VERSION 5.8 ;
BUSBITCHARS "[]" ;
DIVIDERCHAR "/" ;
UNITS
    DATABASE MICRONS 1000 ;
END UNITS

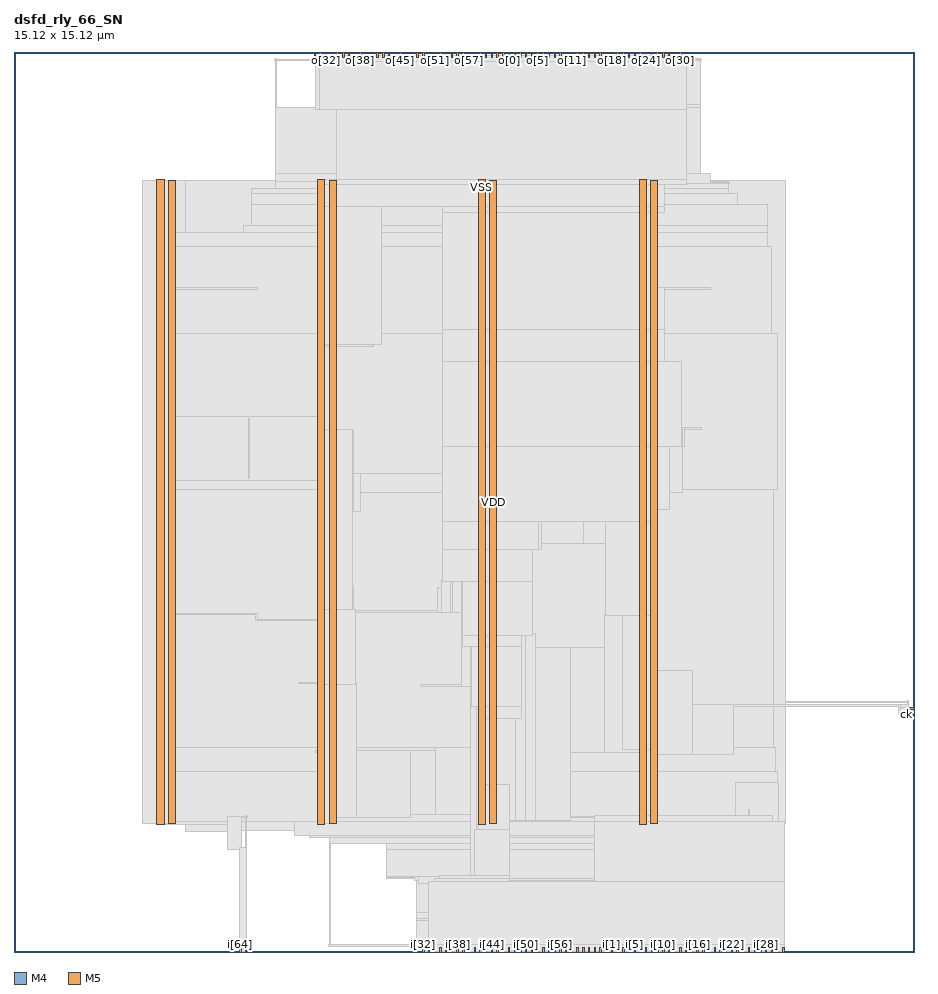
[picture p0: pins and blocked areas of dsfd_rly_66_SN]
MACRO dsfd_rly_66_SN
  FOREIGN dsfd_rly_66_SN 0 0 ;
  CLASS BLOCK ;
  SIZE 15.12 BY 15.12 ;
  PIN ck
    DIRECTION INPUT ;
    USE SIGNAL ;
    PORT
      LAYER M4 ;
        RECT  15.036 3.984 15.12 4.008 ;
    END
  END ck
  PIN i[0]
    DIRECTION INPUT ;
    USE SIGNAL ;
    PORT
      LAYER M5 ;
        RECT  9.936 0 9.96 0.084 ;
    END
  END i[0]
  PIN i[10]
    DIRECTION INPUT ;
    USE SIGNAL ;
    PORT
      LAYER M5 ;
        RECT  10.896 0 10.92 0.084 ;
    END
  END i[10]
  PIN i[11]
    DIRECTION INPUT ;
    USE SIGNAL ;
    PORT
      LAYER M5 ;
        RECT  10.992 0 11.016 0.084 ;
    END
  END i[11]
  PIN i[12]
    DIRECTION INPUT ;
    USE SIGNAL ;
    PORT
      LAYER M5 ;
        RECT  11.088 0 11.112 0.084 ;
    END
  END i[12]
  PIN i[13]
    DIRECTION INPUT ;
    USE SIGNAL ;
    PORT
      LAYER M5 ;
        RECT  11.184 0 11.208 0.084 ;
    END
  END i[13]
  PIN i[14]
    DIRECTION INPUT ;
    USE SIGNAL ;
    PORT
      LAYER M5 ;
        RECT  11.28 0 11.304 0.084 ;
    END
  END i[14]
  PIN i[15]
    DIRECTION INPUT ;
    USE SIGNAL ;
    PORT
      LAYER M5 ;
        RECT  11.376 0 11.4 0.084 ;
    END
  END i[15]
  PIN i[16]
    DIRECTION INPUT ;
    USE SIGNAL ;
    PORT
      LAYER M5 ;
        RECT  11.472 0 11.496 0.084 ;
    END
  END i[16]
  PIN i[17]
    DIRECTION INPUT ;
    USE SIGNAL ;
    PORT
      LAYER M5 ;
        RECT  11.568 0 11.592 0.084 ;
    END
  END i[17]
  PIN i[18]
    DIRECTION INPUT ;
    USE SIGNAL ;
    PORT
      LAYER M5 ;
        RECT  11.664 0 11.688 0.084 ;
    END
  END i[18]
  PIN i[19]
    DIRECTION INPUT ;
    USE SIGNAL ;
    PORT
      LAYER M5 ;
        RECT  11.76 0 11.784 0.084 ;
    END
  END i[19]
  PIN i[1]
    DIRECTION INPUT ;
    USE SIGNAL ;
    PORT
      LAYER M5 ;
        RECT  10.032 0 10.056 0.084 ;
    END
  END i[1]
  PIN i[20]
    DIRECTION INPUT ;
    USE SIGNAL ;
    PORT
      LAYER M5 ;
        RECT  11.856 0 11.88 0.084 ;
    END
  END i[20]
  PIN i[21]
    DIRECTION INPUT ;
    USE SIGNAL ;
    PORT
      LAYER M5 ;
        RECT  11.952 0 11.976 0.084 ;
    END
  END i[21]
  PIN i[22]
    DIRECTION INPUT ;
    USE SIGNAL ;
    PORT
      LAYER M5 ;
        RECT  12.048 0 12.072 0.084 ;
    END
  END i[22]
  PIN i[23]
    DIRECTION INPUT ;
    USE SIGNAL ;
    PORT
      LAYER M5 ;
        RECT  12.144 0 12.168 0.084 ;
    END
  END i[23]
  PIN i[24]
    DIRECTION INPUT ;
    USE SIGNAL ;
    PORT
      LAYER M5 ;
        RECT  12.24 0 12.264 0.084 ;
    END
  END i[24]
  PIN i[25]
    DIRECTION INPUT ;
    USE SIGNAL ;
    PORT
      LAYER M5 ;
        RECT  12.336 0 12.36 0.084 ;
    END
  END i[25]
  PIN i[26]
    DIRECTION INPUT ;
    USE SIGNAL ;
    PORT
      LAYER M5 ;
        RECT  12.432 0 12.456 0.084 ;
    END
  END i[26]
  PIN i[27]
    DIRECTION INPUT ;
    USE SIGNAL ;
    PORT
      LAYER M5 ;
        RECT  12.528 0 12.552 0.084 ;
    END
  END i[27]
  PIN i[28]
    DIRECTION INPUT ;
    USE SIGNAL ;
    PORT
      LAYER M5 ;
        RECT  12.624 0 12.648 0.084 ;
    END
  END i[28]
  PIN i[29]
    DIRECTION INPUT ;
    USE SIGNAL ;
    PORT
      LAYER M5 ;
        RECT  12.72 0 12.744 0.084 ;
    END
  END i[29]
  PIN i[2]
    DIRECTION INPUT ;
    USE SIGNAL ;
    PORT
      LAYER M5 ;
        RECT  10.128 0 10.152 0.084 ;
    END
  END i[2]
  PIN i[30]
    DIRECTION INPUT ;
    USE SIGNAL ;
    PORT
      LAYER M5 ;
        RECT  12.816 0 12.84 0.084 ;
    END
  END i[30]
  PIN i[31]
    DIRECTION INPUT ;
    USE SIGNAL ;
    PORT
      LAYER M5 ;
        RECT  12.912 0 12.936 0.084 ;
    END
  END i[31]
  PIN i[32]
    DIRECTION INPUT ;
    USE SIGNAL ;
    PORT
      LAYER M5 ;
        RECT  6.864 0 6.888 0.084 ;
    END
  END i[32]
  PIN i[33]
    DIRECTION INPUT ;
    USE SIGNAL ;
    PORT
      LAYER M5 ;
        RECT  6.96 0 6.984 0.084 ;
    END
  END i[33]
  PIN i[34]
    DIRECTION INPUT ;
    USE SIGNAL ;
    PORT
      LAYER M5 ;
        RECT  7.056 0 7.08 0.084 ;
    END
  END i[34]
  PIN i[35]
    DIRECTION INPUT ;
    USE SIGNAL ;
    PORT
      LAYER M5 ;
        RECT  7.152 0 7.176 0.084 ;
    END
  END i[35]
  PIN i[36]
    DIRECTION INPUT ;
    USE SIGNAL ;
    PORT
      LAYER M5 ;
        RECT  7.248 0 7.272 0.084 ;
    END
  END i[36]
  PIN i[37]
    DIRECTION INPUT ;
    USE SIGNAL ;
    PORT
      LAYER M5 ;
        RECT  7.344 0 7.368 0.084 ;
    END
  END i[37]
  PIN i[38]
    DIRECTION INPUT ;
    USE SIGNAL ;
    PORT
      LAYER M5 ;
        RECT  7.44 0 7.464 0.084 ;
    END
  END i[38]
  PIN i[39]
    DIRECTION INPUT ;
    USE SIGNAL ;
    PORT
      LAYER M5 ;
        RECT  7.536 0 7.56 0.084 ;
    END
  END i[39]
  PIN i[3]
    DIRECTION INPUT ;
    USE SIGNAL ;
    PORT
      LAYER M5 ;
        RECT  10.224 0 10.248 0.084 ;
    END
  END i[3]
  PIN i[40]
    DIRECTION INPUT ;
    USE SIGNAL ;
    PORT
      LAYER M5 ;
        RECT  7.632 0 7.656 0.084 ;
    END
  END i[40]
  PIN i[41]
    DIRECTION INPUT ;
    USE SIGNAL ;
    PORT
      LAYER M5 ;
        RECT  7.728 0 7.752 0.084 ;
    END
  END i[41]
  PIN i[42]
    DIRECTION INPUT ;
    USE SIGNAL ;
    PORT
      LAYER M5 ;
        RECT  7.824 0 7.848 0.084 ;
    END
  END i[42]
  PIN i[43]
    DIRECTION INPUT ;
    USE SIGNAL ;
    PORT
      LAYER M5 ;
        RECT  7.92 0 7.944 0.084 ;
    END
  END i[43]
  PIN i[44]
    DIRECTION INPUT ;
    USE SIGNAL ;
    PORT
      LAYER M5 ;
        RECT  8.016 0 8.04 0.084 ;
    END
  END i[44]
  PIN i[45]
    DIRECTION INPUT ;
    USE SIGNAL ;
    PORT
      LAYER M5 ;
        RECT  8.112 0 8.136 0.084 ;
    END
  END i[45]
  PIN i[46]
    DIRECTION INPUT ;
    USE SIGNAL ;
    PORT
      LAYER M5 ;
        RECT  8.208 0 8.232 0.084 ;
    END
  END i[46]
  PIN i[47]
    DIRECTION INPUT ;
    USE SIGNAL ;
    PORT
      LAYER M5 ;
        RECT  8.304 0 8.328 0.084 ;
    END
  END i[47]
  PIN i[48]
    DIRECTION INPUT ;
    USE SIGNAL ;
    PORT
      LAYER M5 ;
        RECT  8.4 0 8.424 0.084 ;
    END
  END i[48]
  PIN i[49]
    DIRECTION INPUT ;
    USE SIGNAL ;
    PORT
      LAYER M5 ;
        RECT  8.496 0 8.52 0.084 ;
    END
  END i[49]
  PIN i[4]
    DIRECTION INPUT ;
    USE SIGNAL ;
    PORT
      LAYER M5 ;
        RECT  10.32 0 10.344 0.084 ;
    END
  END i[4]
  PIN i[50]
    DIRECTION INPUT ;
    USE SIGNAL ;
    PORT
      LAYER M5 ;
        RECT  8.592 0 8.616 0.084 ;
    END
  END i[50]
  PIN i[51]
    DIRECTION INPUT ;
    USE SIGNAL ;
    PORT
      LAYER M5 ;
        RECT  8.688 0 8.712 0.084 ;
    END
  END i[51]
  PIN i[52]
    DIRECTION INPUT ;
    USE SIGNAL ;
    PORT
      LAYER M5 ;
        RECT  8.784 0 8.808 0.084 ;
    END
  END i[52]
  PIN i[53]
    DIRECTION INPUT ;
    USE SIGNAL ;
    PORT
      LAYER M5 ;
        RECT  8.88 0 8.904 0.084 ;
    END
  END i[53]
  PIN i[54]
    DIRECTION INPUT ;
    USE SIGNAL ;
    PORT
      LAYER M5 ;
        RECT  8.976 0 9 0.084 ;
    END
  END i[54]
  PIN i[55]
    DIRECTION INPUT ;
    USE SIGNAL ;
    PORT
      LAYER M5 ;
        RECT  9.072 0 9.096 0.084 ;
    END
  END i[55]
  PIN i[56]
    DIRECTION INPUT ;
    USE SIGNAL ;
    PORT
      LAYER M5 ;
        RECT  9.168 0 9.192 0.084 ;
    END
  END i[56]
  PIN i[57]
    DIRECTION INPUT ;
    USE SIGNAL ;
    PORT
      LAYER M5 ;
        RECT  9.264 0 9.288 0.084 ;
    END
  END i[57]
  PIN i[58]
    DIRECTION INPUT ;
    USE SIGNAL ;
    PORT
      LAYER M5 ;
        RECT  9.36 0 9.384 0.084 ;
    END
  END i[58]
  PIN i[59]
    DIRECTION INPUT ;
    USE SIGNAL ;
    PORT
      LAYER M5 ;
        RECT  9.456 0 9.48 0.084 ;
    END
  END i[59]
  PIN i[5]
    DIRECTION INPUT ;
    USE SIGNAL ;
    PORT
      LAYER M5 ;
        RECT  10.416 0 10.44 0.084 ;
    END
  END i[5]
  PIN i[60]
    DIRECTION INPUT ;
    USE SIGNAL ;
    PORT
      LAYER M5 ;
        RECT  9.552 0 9.576 0.084 ;
    END
  END i[60]
  PIN i[61]
    DIRECTION INPUT ;
    USE SIGNAL ;
    PORT
      LAYER M5 ;
        RECT  9.648 0 9.672 0.084 ;
    END
  END i[61]
  PIN i[62]
    DIRECTION INPUT ;
    USE SIGNAL ;
    PORT
      LAYER M5 ;
        RECT  9.744 0 9.768 0.084 ;
    END
  END i[62]
  PIN i[63]
    DIRECTION INPUT ;
    USE SIGNAL ;
    PORT
      LAYER M5 ;
        RECT  9.84 0 9.864 0.084 ;
    END
  END i[63]
  PIN i[64]
    DIRECTION INPUT ;
    USE SIGNAL ;
    PORT
      LAYER M5 ;
        RECT  3.792 0 3.816 0.084 ;
    END
  END i[64]
  PIN i[65]
    DIRECTION INPUT ;
    USE SIGNAL ;
    PORT
      LAYER M5 ;
        RECT  3.888 0 3.912 0.084 ;
    END
  END i[65]
  PIN i[6]
    DIRECTION INPUT ;
    USE SIGNAL ;
    PORT
      LAYER M5 ;
        RECT  10.512 0 10.536 0.084 ;
    END
  END i[6]
  PIN i[7]
    DIRECTION INPUT ;
    USE SIGNAL ;
    PORT
      LAYER M5 ;
        RECT  10.608 0 10.632 0.084 ;
    END
  END i[7]
  PIN i[8]
    DIRECTION INPUT ;
    USE SIGNAL ;
    PORT
      LAYER M5 ;
        RECT  10.704 0 10.728 0.084 ;
    END
  END i[8]
  PIN i[9]
    DIRECTION INPUT ;
    USE SIGNAL ;
    PORT
      LAYER M5 ;
        RECT  10.8 0 10.824 0.084 ;
    END
  END i[9]
  PIN o[0]
    DIRECTION OUTPUT ;
    USE SIGNAL ;
    PORT
      LAYER M5 ;
        RECT  8.304 15.036 8.328 15.12 ;
    END
  END o[0]
  PIN o[10]
    DIRECTION OUTPUT ;
    USE SIGNAL ;
    PORT
      LAYER M5 ;
        RECT  9.264 15.036 9.288 15.12 ;
    END
  END o[10]
  PIN o[11]
    DIRECTION OUTPUT ;
    USE SIGNAL ;
    PORT
      LAYER M5 ;
        RECT  9.36 15.036 9.384 15.12 ;
    END
  END o[11]
  PIN o[12]
    DIRECTION OUTPUT ;
    USE SIGNAL ;
    PORT
      LAYER M5 ;
        RECT  9.456 15.036 9.48 15.12 ;
    END
  END o[12]
  PIN o[13]
    DIRECTION OUTPUT ;
    USE SIGNAL ;
    PORT
      LAYER M5 ;
        RECT  9.552 15.036 9.576 15.12 ;
    END
  END o[13]
  PIN o[14]
    DIRECTION OUTPUT ;
    USE SIGNAL ;
    PORT
      LAYER M5 ;
        RECT  9.648 15.036 9.672 15.12 ;
    END
  END o[14]
  PIN o[15]
    DIRECTION OUTPUT ;
    USE SIGNAL ;
    PORT
      LAYER M5 ;
        RECT  9.744 15.036 9.768 15.12 ;
    END
  END o[15]
  PIN o[16]
    DIRECTION OUTPUT ;
    USE SIGNAL ;
    PORT
      LAYER M5 ;
        RECT  9.84 15.036 9.864 15.12 ;
    END
  END o[16]
  PIN o[17]
    DIRECTION OUTPUT ;
    USE SIGNAL ;
    PORT
      LAYER M5 ;
        RECT  9.936 15.036 9.96 15.12 ;
    END
  END o[17]
  PIN o[18]
    DIRECTION OUTPUT ;
    USE SIGNAL ;
    PORT
      LAYER M5 ;
        RECT  10.032 15.036 10.056 15.12 ;
    END
  END o[18]
  PIN o[19]
    DIRECTION OUTPUT ;
    USE SIGNAL ;
    PORT
      LAYER M5 ;
        RECT  10.128 15.036 10.152 15.12 ;
    END
  END o[19]
  PIN o[1]
    DIRECTION OUTPUT ;
    USE SIGNAL ;
    PORT
      LAYER M5 ;
        RECT  8.4 15.036 8.424 15.12 ;
    END
  END o[1]
  PIN o[20]
    DIRECTION OUTPUT ;
    USE SIGNAL ;
    PORT
      LAYER M5 ;
        RECT  10.224 15.036 10.248 15.12 ;
    END
  END o[20]
  PIN o[21]
    DIRECTION OUTPUT ;
    USE SIGNAL ;
    PORT
      LAYER M5 ;
        RECT  10.32 15.036 10.344 15.12 ;
    END
  END o[21]
  PIN o[22]
    DIRECTION OUTPUT ;
    USE SIGNAL ;
    PORT
      LAYER M5 ;
        RECT  10.416 15.036 10.44 15.12 ;
    END
  END o[22]
  PIN o[23]
    DIRECTION OUTPUT ;
    USE SIGNAL ;
    PORT
      LAYER M5 ;
        RECT  10.512 15.036 10.536 15.12 ;
    END
  END o[23]
  PIN o[24]
    DIRECTION OUTPUT ;
    USE SIGNAL ;
    PORT
      LAYER M5 ;
        RECT  10.608 15.036 10.632 15.12 ;
    END
  END o[24]
  PIN o[25]
    DIRECTION OUTPUT ;
    USE SIGNAL ;
    PORT
      LAYER M5 ;
        RECT  10.704 15.036 10.728 15.12 ;
    END
  END o[25]
  PIN o[26]
    DIRECTION OUTPUT ;
    USE SIGNAL ;
    PORT
      LAYER M5 ;
        RECT  10.8 15.036 10.824 15.12 ;
    END
  END o[26]
  PIN o[27]
    DIRECTION OUTPUT ;
    USE SIGNAL ;
    PORT
      LAYER M5 ;
        RECT  10.896 15.036 10.92 15.12 ;
    END
  END o[27]
  PIN o[28]
    DIRECTION OUTPUT ;
    USE SIGNAL ;
    PORT
      LAYER M5 ;
        RECT  10.992 15.036 11.016 15.12 ;
    END
  END o[28]
  PIN o[29]
    DIRECTION OUTPUT ;
    USE SIGNAL ;
    PORT
      LAYER M5 ;
        RECT  11.088 15.036 11.112 15.12 ;
    END
  END o[29]
  PIN o[2]
    DIRECTION OUTPUT ;
    USE SIGNAL ;
    PORT
      LAYER M5 ;
        RECT  8.496 15.036 8.52 15.12 ;
    END
  END o[2]
  PIN o[30]
    DIRECTION OUTPUT ;
    USE SIGNAL ;
    PORT
      LAYER M5 ;
        RECT  11.184 15.036 11.208 15.12 ;
    END
  END o[30]
  PIN o[31]
    DIRECTION OUTPUT ;
    USE SIGNAL ;
    PORT
      LAYER M5 ;
        RECT  11.28 15.036 11.304 15.12 ;
    END
  END o[31]
  PIN o[32]
    DIRECTION OUTPUT ;
    USE SIGNAL ;
    PORT
      LAYER M5 ;
        RECT  5.232 15.036 5.256 15.12 ;
    END
  END o[32]
  PIN o[33]
    DIRECTION OUTPUT ;
    USE SIGNAL ;
    PORT
      LAYER M5 ;
        RECT  5.328 15.036 5.352 15.12 ;
    END
  END o[33]
  PIN o[34]
    DIRECTION OUTPUT ;
    USE SIGNAL ;
    PORT
      LAYER M5 ;
        RECT  5.424 15.036 5.448 15.12 ;
    END
  END o[34]
  PIN o[35]
    DIRECTION OUTPUT ;
    USE SIGNAL ;
    PORT
      LAYER M5 ;
        RECT  5.52 15.036 5.544 15.12 ;
    END
  END o[35]
  PIN o[36]
    DIRECTION OUTPUT ;
    USE SIGNAL ;
    PORT
      LAYER M5 ;
        RECT  5.616 15.036 5.64 15.12 ;
    END
  END o[36]
  PIN o[37]
    DIRECTION OUTPUT ;
    USE SIGNAL ;
    PORT
      LAYER M5 ;
        RECT  5.712 15.036 5.736 15.12 ;
    END
  END o[37]
  PIN o[38]
    DIRECTION OUTPUT ;
    USE SIGNAL ;
    PORT
      LAYER M5 ;
        RECT  5.808 15.036 5.832 15.12 ;
    END
  END o[38]
  PIN o[39]
    DIRECTION OUTPUT ;
    USE SIGNAL ;
    PORT
      LAYER M5 ;
        RECT  5.904 15.036 5.928 15.12 ;
    END
  END o[39]
  PIN o[3]
    DIRECTION OUTPUT ;
    USE SIGNAL ;
    PORT
      LAYER M5 ;
        RECT  8.592 15.036 8.616 15.12 ;
    END
  END o[3]
  PIN o[40]
    DIRECTION OUTPUT ;
    USE SIGNAL ;
    PORT
      LAYER M5 ;
        RECT  6 15.036 6.024 15.12 ;
    END
  END o[40]
  PIN o[41]
    DIRECTION OUTPUT ;
    USE SIGNAL ;
    PORT
      LAYER M5 ;
        RECT  6.096 15.036 6.12 15.12 ;
    END
  END o[41]
  PIN o[42]
    DIRECTION OUTPUT ;
    USE SIGNAL ;
    PORT
      LAYER M5 ;
        RECT  6.192 15.036 6.216 15.12 ;
    END
  END o[42]
  PIN o[43]
    DIRECTION OUTPUT ;
    USE SIGNAL ;
    PORT
      LAYER M5 ;
        RECT  6.288 15.036 6.312 15.12 ;
    END
  END o[43]
  PIN o[44]
    DIRECTION OUTPUT ;
    USE SIGNAL ;
    PORT
      LAYER M5 ;
        RECT  6.384 15.036 6.408 15.12 ;
    END
  END o[44]
  PIN o[45]
    DIRECTION OUTPUT ;
    USE SIGNAL ;
    PORT
      LAYER M5 ;
        RECT  6.48 15.036 6.504 15.12 ;
    END
  END o[45]
  PIN o[46]
    DIRECTION OUTPUT ;
    USE SIGNAL ;
    PORT
      LAYER M5 ;
        RECT  6.576 15.036 6.6 15.12 ;
    END
  END o[46]
  PIN o[47]
    DIRECTION OUTPUT ;
    USE SIGNAL ;
    PORT
      LAYER M5 ;
        RECT  6.672 15.036 6.696 15.12 ;
    END
  END o[47]
  PIN o[48]
    DIRECTION OUTPUT ;
    USE SIGNAL ;
    PORT
      LAYER M5 ;
        RECT  6.768 15.036 6.792 15.12 ;
    END
  END o[48]
  PIN o[49]
    DIRECTION OUTPUT ;
    USE SIGNAL ;
    PORT
      LAYER M5 ;
        RECT  6.864 15.036 6.888 15.12 ;
    END
  END o[49]
  PIN o[4]
    DIRECTION OUTPUT ;
    USE SIGNAL ;
    PORT
      LAYER M5 ;
        RECT  8.688 15.036 8.712 15.12 ;
    END
  END o[4]
  PIN o[50]
    DIRECTION OUTPUT ;
    USE SIGNAL ;
    PORT
      LAYER M5 ;
        RECT  6.96 15.036 6.984 15.12 ;
    END
  END o[50]
  PIN o[51]
    DIRECTION OUTPUT ;
    USE SIGNAL ;
    PORT
      LAYER M5 ;
        RECT  7.056 15.036 7.08 15.12 ;
    END
  END o[51]
  PIN o[52]
    DIRECTION OUTPUT ;
    USE SIGNAL ;
    PORT
      LAYER M5 ;
        RECT  7.152 15.036 7.176 15.12 ;
    END
  END o[52]
  PIN o[53]
    DIRECTION OUTPUT ;
    USE SIGNAL ;
    PORT
      LAYER M5 ;
        RECT  7.248 15.036 7.272 15.12 ;
    END
  END o[53]
  PIN o[54]
    DIRECTION OUTPUT ;
    USE SIGNAL ;
    PORT
      LAYER M5 ;
        RECT  7.344 15.036 7.368 15.12 ;
    END
  END o[54]
  PIN o[55]
    DIRECTION OUTPUT ;
    USE SIGNAL ;
    PORT
      LAYER M5 ;
        RECT  7.44 15.036 7.464 15.12 ;
    END
  END o[55]
  PIN o[56]
    DIRECTION OUTPUT ;
    USE SIGNAL ;
    PORT
      LAYER M5 ;
        RECT  7.536 15.036 7.56 15.12 ;
    END
  END o[56]
  PIN o[57]
    DIRECTION OUTPUT ;
    USE SIGNAL ;
    PORT
      LAYER M5 ;
        RECT  7.632 15.036 7.656 15.12 ;
    END
  END o[57]
  PIN o[58]
    DIRECTION OUTPUT ;
    USE SIGNAL ;
    PORT
      LAYER M5 ;
        RECT  7.728 15.036 7.752 15.12 ;
    END
  END o[58]
  PIN o[59]
    DIRECTION OUTPUT ;
    USE SIGNAL ;
    PORT
      LAYER M5 ;
        RECT  7.824 15.036 7.848 15.12 ;
    END
  END o[59]
  PIN o[5]
    DIRECTION OUTPUT ;
    USE SIGNAL ;
    PORT
      LAYER M5 ;
        RECT  8.784 15.036 8.808 15.12 ;
    END
  END o[5]
  PIN o[60]
    DIRECTION OUTPUT ;
    USE SIGNAL ;
    PORT
      LAYER M5 ;
        RECT  7.92 15.036 7.944 15.12 ;
    END
  END o[60]
  PIN o[61]
    DIRECTION OUTPUT ;
    USE SIGNAL ;
    PORT
      LAYER M5 ;
        RECT  8.016 15.036 8.04 15.12 ;
    END
  END o[61]
  PIN o[62]
    DIRECTION OUTPUT ;
    USE SIGNAL ;
    PORT
      LAYER M5 ;
        RECT  8.112 15.036 8.136 15.12 ;
    END
  END o[62]
  PIN o[63]
    DIRECTION OUTPUT ;
    USE SIGNAL ;
    PORT
      LAYER M5 ;
        RECT  8.208 15.036 8.232 15.12 ;
    END
  END o[63]
  PIN o[64]
    DIRECTION OUTPUT ;
    USE SIGNAL ;
    PORT
      LAYER M5 ;
        RECT  5.04 15.036 5.064 15.12 ;
    END
  END o[64]
  PIN o[65]
    DIRECTION OUTPUT ;
    USE SIGNAL ;
    PORT
      LAYER M5 ;
        RECT  5.136 15.036 5.16 15.12 ;
    END
  END o[65]
  PIN o[6]
    DIRECTION OUTPUT ;
    USE SIGNAL ;
    PORT
      LAYER M5 ;
        RECT  8.88 15.036 8.904 15.12 ;
    END
  END o[6]
  PIN o[7]
    DIRECTION OUTPUT ;
    USE SIGNAL ;
    PORT
      LAYER M5 ;
        RECT  8.976 15.036 9 15.12 ;
    END
  END o[7]
  PIN o[8]
    DIRECTION OUTPUT ;
    USE SIGNAL ;
    PORT
      LAYER M5 ;
        RECT  9.072 15.036 9.096 15.12 ;
    END
  END o[8]
  PIN o[9]
    DIRECTION OUTPUT ;
    USE SIGNAL ;
    PORT
      LAYER M5 ;
        RECT  9.168 15.036 9.192 15.12 ;
    END
  END o[9]
  PIN rs
    DIRECTION INPUT ;
    USE SIGNAL ;
    PORT
      LAYER M4 ;
        RECT  15.036 4.08 15.12 4.104 ;
    END
  END rs
  PIN VDD
    DIRECTION INOUT ;
    USE POWER ;
    PORT
      LAYER M5 ;
        RECT  10.692 2.151 10.812 12.969 ;
        RECT  7.992 2.151 8.112 12.969 ;
        RECT  5.292 2.151 5.412 12.969 ;
        RECT  2.592 2.151 2.712 12.969 ;
    END
  END VDD
  PIN VSS
    DIRECTION INOUT ;
    USE GROUND ;
    PORT
      LAYER M5 ;
        RECT  10.5 2.137 10.62 12.983 ;
        RECT  7.8 2.137 7.92 12.983 ;
        RECT  5.1 2.137 5.22 12.983 ;
        RECT  2.4 2.137 2.52 12.983 ;
    END
  END VSS
  OBS
    LAYER RVTN ;
     RECT  2.16 2.16 12.96 2.295 ;
     RECT  2.16 2.565 12.96 2.835 ;
     RECT  2.16 3.105 12.96 3.375 ;
     RECT  2.16 3.645 12.96 3.915 ;
     RECT  2.16 4.185 12.96 4.455 ;
     RECT  2.16 4.725 12.96 4.995 ;
     RECT  2.16 5.265 12.96 5.535 ;
     RECT  2.16 5.805 12.96 6.075 ;
     RECT  2.16 6.345 12.96 6.615 ;
     RECT  2.16 6.885 12.96 7.155 ;
     RECT  2.16 7.425 12.96 7.695 ;
     RECT  2.16 7.965 12.96 8.235 ;
     RECT  2.16 8.505 12.96 8.775 ;
     RECT  2.16 9.045 12.96 9.315 ;
     RECT  2.16 9.585 12.96 9.855 ;
     RECT  2.16 10.125 12.96 10.395 ;
     RECT  2.16 10.665 12.96 10.935 ;
     RECT  2.16 11.205 12.96 11.475 ;
     RECT  2.16 11.745 12.96 12.015 ;
     RECT  2.16 12.285 12.96 12.555 ;
     RECT  2.16 12.825 12.96 12.96 ;
    LAYER RVTP ;
     RECT  2.16 2.295 12.96 2.565 ;
     RECT  2.16 2.835 12.96 3.105 ;
     RECT  2.16 3.375 12.96 3.645 ;
     RECT  2.16 3.915 12.96 4.185 ;
     RECT  2.16 4.455 12.96 4.725 ;
     RECT  2.16 4.995 12.96 5.265 ;
     RECT  2.16 5.535 12.96 5.805 ;
     RECT  2.16 6.075 12.96 6.345 ;
     RECT  2.16 6.615 12.96 6.885 ;
     RECT  2.16 7.155 12.96 7.425 ;
     RECT  2.16 7.695 12.96 7.965 ;
     RECT  2.16 8.235 12.96 8.505 ;
     RECT  2.16 8.775 12.96 9.045 ;
     RECT  2.16 9.315 12.96 9.585 ;
     RECT  2.16 9.855 12.96 10.125 ;
     RECT  2.16 10.395 12.96 10.665 ;
     RECT  2.16 10.935 12.96 11.205 ;
     RECT  2.16 11.475 12.96 11.745 ;
     RECT  2.16 12.015 12.96 12.285 ;
     RECT  2.16 12.555 12.96 12.825 ;
    LAYER M1 ;
     RECT  2.16 2.151 12.96 12.969 ;
    LAYER M2 ;
     RECT  2.16 2.151 2.875 12.969 ;
     RECT  2.875 2.034 4.711 12.969 ;
     RECT  4.711 1.962 4.963 12.969 ;
     RECT  4.963 1.926 5.647 12.969 ;
     RECT  5.647 1.836 6.835 12.969 ;
     RECT  6.835 1.764 8.411 12.969 ;
     RECT  8.411 1.881 9.059 12.969 ;
     RECT  9.059 1.962 9.347 12.969 ;
     RECT  9.347 2.034 11.471 12.969 ;
     RECT  11.471 2.151 12.96 12.969 ;
     RECT  12.96 4.194 15.035 4.212 ;
    LAYER M3 ;
     RECT  7.38 0.091 7.398 0.139 ;
     RECT  10.476 0.091 10.494 0.475 ;
     RECT  6.768 0.139 7.398 0.523 ;
     RECT  8.136 0.091 9.378 0.523 ;
     RECT  10.26 0.475 10.854 0.523 ;
     RECT  6.768 0.523 10.854 0.571 ;
     RECT  11.916 0.091 11.934 0.571 ;
     RECT  6.768 0.571 12.15 0.667 ;
     RECT  6.768 0.667 12.582 1.195 ;
     RECT  6.732 1.195 12.582 1.243 ;
     RECT  6.264 1.243 12.582 1.723 ;
     RECT  5.292 0.091 5.31 1.831 ;
     RECT  6.264 1.723 12.834 1.831 ;
     RECT  5.292 1.831 12.834 1.921 ;
     RECT  4.968 1.921 12.834 1.957 ;
     RECT  3.6 1.723 3.618 2.029 ;
     RECT  2.88 2.029 3.618 2.143 ;
     RECT  2.415 2.143 3.618 2.191 ;
     RECT  4.716 1.957 12.834 2.191 ;
     RECT  2.415 2.191 12.834 3.029 ;
     RECT  2.415 3.029 12.798 3.443 ;
     RECT  14.868 3.979 14.886 4.075 ;
     RECT  14.868 4.075 15.03 4.157 ;
     RECT  15.012 4.157 15.03 4.217 ;
     RECT  2.415 3.443 12.762 7.771 ;
     RECT  2.415 7.771 12.834 10.391 ;
     RECT  2.415 10.391 12.726 11.849 ;
     RECT  2.415 11.849 12.654 12.083 ;
     RECT  3.852 12.083 12.654 12.209 ;
     RECT  3.996 12.209 12.654 12.551 ;
     RECT  2.415 12.083 2.697 12.707 ;
     RECT  3.996 12.551 12.15 12.749 ;
     RECT  3.996 12.749 12.006 12.821 ;
     RECT  4.392 12.821 12.006 12.941 ;
     RECT  2.415 12.707 2.505 12.977 ;
     RECT  4.392 12.941 11.682 13.085 ;
     RECT  4.392 13.085 11.538 14.189 ;
     RECT  5.256 14.189 11.538 14.237 ;
     RECT  5.436 14.237 5.886 14.285 ;
     RECT  4.392 14.189 4.41 15.005 ;
     RECT  5.868 14.285 5.886 15.005 ;
     RECT  6.876 14.237 10.134 15.005 ;
     RECT  10.872 14.237 11.538 15.005 ;
    LAYER M4 ;
     RECT  2.408 2.148 2.512 12.972 ;
     RECT  2.512 2.418 2.704 12.702 ;
     RECT  3.589 1.728 3.827 2.28 ;
     RECT  3.827 2.256 3.923 2.28 ;
     RECT  2.704 5.664 4.057 5.688 ;
     RECT  4.057 5.568 4.097 5.688 ;
     RECT  2.704 11.136 4.097 11.16 ;
     RECT  4.381 14.976 5.065 15 ;
     RECT  5.065 3.36 5.101 3.384 ;
     RECT  5.101 2.88 5.108 3.384 ;
     RECT  4.777 4.512 5.108 4.536 ;
     RECT  4.097 5.568 5.108 5.592 ;
     RECT  2.704 7.92 5.108 9 ;
     RECT  5.108 2.148 5.212 12.972 ;
     RECT  5.212 2.256 5.404 12.972 ;
     RECT  5.404 12 5.413 12.972 ;
     RECT  5.065 14.16 5.413 15 ;
     RECT  5.404 5.568 5.465 6.12 ;
     RECT  5.413 12 5.645 15 ;
     RECT  5.465 5.712 5.699 6.12 ;
     RECT  5.404 7.392 5.699 8.76 ;
     RECT  5.404 2.256 5.753 4.536 ;
     RECT  5.645 12.48 5.753 15 ;
     RECT  5.699 7.392 5.825 8.04 ;
     RECT  5.404 10.176 6.041 10.248 ;
     RECT  6.041 10.224 6.179 10.248 ;
     RECT  5.753 12.528 6.545 15 ;
     RECT  5.753 2.256 6.653 3.384 ;
     RECT  6.253 1.248 6.721 1.272 ;
     RECT  5.281 0.096 6.757 0.12 ;
     RECT  6.721 1.2 6.793 1.272 ;
     RECT  6.653 2.304 7.081 3.384 ;
     RECT  5.699 5.712 7.117 5.736 ;
     RECT  7.117 5.712 7.189 6.12 ;
     RECT  6.545 12.528 7.261 12.552 ;
     RECT  6.757 0.096 7.333 0.168 ;
     RECT  6.793 1.152 7.333 1.272 ;
     RECT  7.189 5.712 7.333 6.264 ;
     RECT  7.333 5.712 7.361 6.696 ;
     RECT  5.825 7.728 7.361 8.04 ;
     RECT  7.237 9.936 7.477 9.96 ;
     RECT  7.477 9.936 7.513 10.872 ;
     RECT  6.829 4.464 7.525 4.488 ;
     RECT  7.361 5.712 7.525 8.04 ;
     RECT  7.081 2.304 7.669 3.432 ;
     RECT  7.525 4.464 7.669 8.04 ;
     RECT  7.333 0.096 7.676 1.272 ;
     RECT  7.669 2.304 7.676 8.04 ;
     RECT  7.676 0.096 7.763 8.04 ;
     RECT  7.763 2.148 7.808 8.04 ;
     RECT  7.513 9.552 7.808 10.872 ;
     RECT  7.261 12 7.808 12.552 ;
     RECT  6.545 13.536 7.808 15 ;
     RECT  7.808 2.148 7.912 15 ;
     RECT  7.912 2.208 8.104 15 ;
     RECT  8.104 2.208 8.417 9.144 ;
     RECT  8.104 12 8.417 15 ;
     RECT  8.417 2.208 8.597 9.096 ;
     RECT  8.597 2.208 8.764 5.352 ;
     RECT  8.597 6.768 8.857 9.096 ;
     RECT  8.104 10.848 9.029 10.872 ;
     RECT  8.417 12.528 9.137 15 ;
     RECT  8.764 2.208 9.353 5.112 ;
     RECT  8.857 6.864 9.565 9.096 ;
     RECT  9.137 13.632 9.605 15 ;
     RECT  9.137 12.528 9.673 12.648 ;
     RECT  9.673 12 9.817 12.648 ;
     RECT  9.353 3.36 9.917 5.112 ;
     RECT  9.565 6.864 9.961 9.672 ;
     RECT  9.817 11.376 10.117 12.648 ;
     RECT  7.763 0.096 10.451 1.176 ;
     RECT  9.353 2.256 10.508 2.28 ;
     RECT  9.917 3.36 10.508 5.688 ;
     RECT  9.961 6.72 10.508 9.672 ;
     RECT  10.117 11.376 10.508 13.128 ;
     RECT  10.451 0.096 10.549 0.648 ;
     RECT  10.508 2.148 10.645 13.128 ;
     RECT  10.645 1.728 10.804 13.128 ;
     RECT  10.804 12.432 10.835 13.128 ;
     RECT  10.804 9.888 10.931 11.16 ;
     RECT  10.835 12.432 10.931 13.08 ;
     RECT  10.804 7.44 11.009 8.808 ;
     RECT  9.605 14.208 11.045 15 ;
     RECT  10.931 9.888 11.219 9.912 ;
     RECT  11.009 7.728 11.225 8.808 ;
     RECT  11.225 8.496 11.26 8.808 ;
     RECT  10.549 0.48 11.315 0.648 ;
     RECT  10.804 3.312 11.405 4.728 ;
     RECT  11.26 8.784 11.549 8.808 ;
     RECT  11.045 14.976 11.549 15 ;
     RECT  10.931 11.136 11.693 11.16 ;
     RECT  10.931 12.912 11.693 13.08 ;
     RECT  11.315 0.48 11.905 0.6 ;
     RECT  11.693 12.912 12.017 12.936 ;
     RECT  11.405 3.312 12.089 4.152 ;
     RECT  10.804 1.728 12.121 2.28 ;
     RECT  11.905 0.096 12.275 0.6 ;
     RECT  12.509 0.672 12.593 0.696 ;
     RECT  12.121 1.728 12.845 2.856 ;
     RECT  12.845 1.728 12.889 2.184 ;
     RECT  12.889 2.16 12.947 2.184 ;
     RECT  12.089 4.128 14.857 4.152 ;
     RECT  14.857 3.984 14.897 4.152 ;
     RECT  14.897 3.984 15.084 4.104 ;
    LAYER M5 ;
     RECT  6.864 0.016 12.936 0.131 ;
     RECT  6.96 0.131 12.936 1.187 ;
     RECT  7.056 1.187 8.328 1.235 ;
     RECT  7.152 1.235 8.328 1.283 ;
     RECT  3.792 0.016 3.912 1.763 ;
     RECT  7.728 1.283 8.328 2.051 ;
     RECT  2.4 2.137 2.52 2.151 ;
     RECT  5.1 2.137 5.22 2.151 ;
     RECT  9.744 1.187 12.936 2.195 ;
     RECT  3.888 1.763 3.912 2.291 ;
     RECT  9.744 2.195 12.744 2.291 ;
     RECT  12.336 2.291 12.36 2.387 ;
     RECT  7.8 2.051 8.328 2.819 ;
     RECT  10.5 2.291 10.812 3.397 ;
     RECT  7.8 2.819 8.112 3.925 ;
     RECT  7.8 3.925 8.52 4.117 ;
     RECT  5.1 2.151 5.412 4.501 ;
     RECT  7.68 4.117 8.52 5.125 ;
     RECT  7.536 5.125 8.52 5.317 ;
     RECT  10.224 3.397 10.812 5.653 ;
     RECT  5.1 4.501 5.736 5.747 ;
     RECT  7.536 5.317 8.712 6.229 ;
     RECT  7.2 6.229 8.712 6.757 ;
     RECT  7.2 6.757 8.808 7.237 ;
     RECT  9.936 5.653 10.812 7.237 ;
     RECT  7.2 7.237 10.812 8.485 ;
     RECT  5.1 5.747 5.688 8.771 ;
     RECT  3.936 7.957 3.96 8.963 ;
     RECT  7.2 8.485 11.208 9.923 ;
     RECT  5.1 8.771 5.412 10.165 ;
     RECT  5.1 10.165 6.024 10.213 ;
     RECT  7.2 9.923 10.92 10.451 ;
     RECT  7.2 10.451 10.812 12.421 ;
     RECT  5.1 10.213 6.168 12.517 ;
     RECT  7.2 12.421 10.92 12.517 ;
     RECT  5.1 12.517 10.92 12.901 ;
     RECT  2.4 2.151 2.712 12.969 ;
     RECT  2.4 12.969 2.52 12.983 ;
     RECT  5.1 12.901 11.304 12.983 ;
     RECT  5.424 12.983 11.304 14.149 ;
     RECT  5.136 14.149 11.304 14.965 ;
     RECT  5.04 14.965 11.304 15.056 ;
  END
END dsfd_rly_66_SN
END LIBRARY
